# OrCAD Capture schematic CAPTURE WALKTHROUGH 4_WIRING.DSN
size A; title: Capture Walkthrough; rev: A; company: EMA Design Automation; note: EMA-12345678; note: 225 Tech Park Dr; note: Rochester, NY

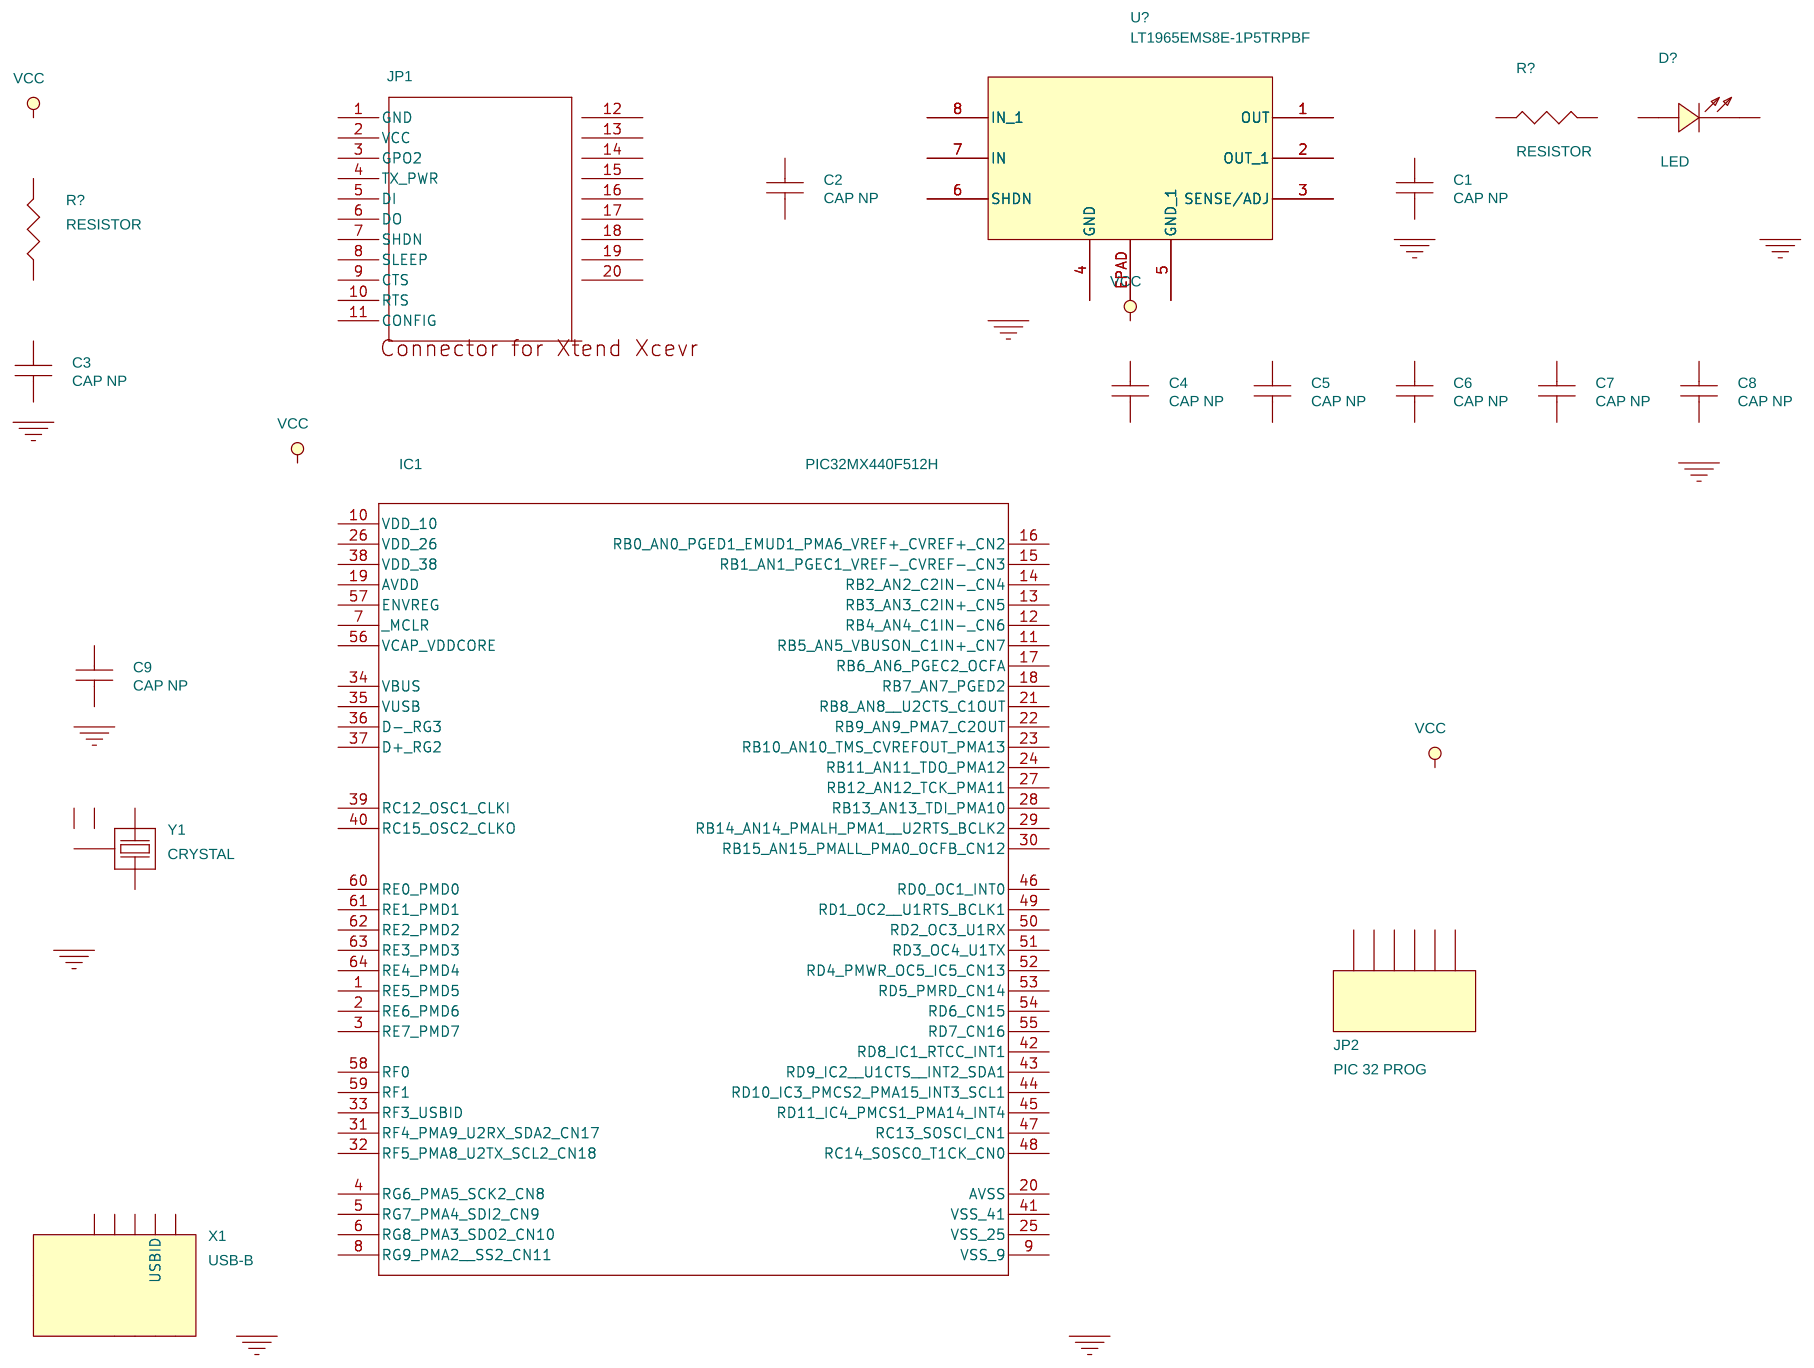
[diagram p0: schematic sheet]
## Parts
C1  CAP NP
C2  CAP NP
C3  CAP NP
C4  CAP NP
C5  CAP NP
C6  CAP NP
C7  CAP NP
C8  CAP NP
C9  CAP NP
D?#1  LED
IC1  PIC32MX440F512H  [sqfp-s-10x10-64]
JP1  XTEND-DIGI-MODEM  [xtend-digi-modem]
JP2  PIC 32 PROG  [1x06_lock]
R?#3  RESISTOR
R?#4  RESISTOR
U?#2  LT1965EMS8E-1P5TRPBF  [MSOP-EP08_3X3_ADI]
X1  USB-B  [USB-MICROB]
Y1  CRYSTAL  [crystal-smd]

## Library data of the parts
C1-C9 = CAP_NP
D?#1 = LED
IC1 = PIC32MX440F512H
JP1 = XTEND-DIGI-MODEM
JP2 = M06_LOCK
R?#3 R?#4 = RESISTOR
U?#2 = LT1965EMS8E-1P5TRPBF_0: 1.1A, Low Noise, Low Dropout Linear Regulator; Category: PMIC - Voltage Regulators - Linear; Distributor: Digi-Key; Distributor_PN: LT1965EMS8E-1.5#TRPBF-ND; MPN: LT1965EMS8E-1.5#TRPBF; Manufacturer: Analog Devices Inc; Mounting_Type: Surface Mount; Operating_Temperature: -40掳C ~ 125掳C; Package_Case: 8-TSSOP, 8-MSOP (0.118", 3.00mm Width) Exposed Pad; Package_Category: Tape & Reel (TR); ROHS: false; Status: Active; Supplier_Device_Package: 8-MSOP-EP
X1 = USB-MICROB
Y1 = CRYSTAL

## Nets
GND: U?#2.4(GND)
GND_1: U?#2.5(GND_1)

Not connected (* = marked no-connect by the designer): C1 1 2; C2 1 2; C3 1 2; C4 1 2; C5 1 2; C6 1 2; C7 1 2; C8 1 2; C9 1 2; D?#1 1(CATHODE) 2(ANODE); IC1 1(RE5_PMD5) 2(RE6_PMD6) 3(RE7_PMD7) 4(RG6_PMA5_SCK2_CN8) 5(RG7_PMA4_SDI2_CN9) 6(RG8_PMA3_SDO2_CN10) 7(_MCLR) 8(RG9_PMA2__SS2_CN11) 9(VSS) 10(VDD) 11(RB5_AN5_VBUSON_C1IN+_CN7) 12(RB4_AN4_C1IN-_CN6) 13(RB3_AN3_C2IN+_CN5) 14(RB2_AN2_C2IN-_CN4) 15(RB1_AN1_PGEC1_VREF-_CVREF-_CN3) 16(RB0_AN0_PGED1_EMUD1_PMA6_VREF+_CVREF+_CN2) 17(RB6_AN6_PGEC2_OCFA) 18(RB7_AN7_PGED2) 19(AVDD) 20(AVSS) 21(RB8_AN8__U2CTS_C1OUT) 22(RB9_AN9_PMA7_C2OUT) 23(RB10_AN10_TMS_CVREFOUT_PMA13) 24(RB11_AN11_TDO_PMA12) 25(VSS) 26(VDD) 27(RB12_AN12_TCK_PMA11) 28(RB13_AN13_TDI_PMA10) 29(RB14_AN14_PMALH_PMA1__U2RTS_BCLK2) 30(RB15_AN15_PMALL_PMA0_OCFB_CN12) 31(RF4_PMA9_U2RX_SDA2_CN17) 32(RF5_PMA8_U2TX_SCL2_CN18) 33(RF3_USBID) 34(VBUS) 35(VUSB) 36(D-_RG3) 37(D+_RG2) 38(VDD) 39(RC12_OSC1_CLKI) 40(RC15_OSC2_CLKO) 41(VSS) 42(RD8_IC1_RTCC_INT1) 43(RD9_IC2__U1CTS__INT2_SDA1) 44(RD10_IC3_PMCS2_PMA15_INT3_SCL1) 45(RD11_IC4_PMCS1_PMA14_INT4) 46(RD0_OC1_INT0) 47(RC13_SOSCI_CN1) 48(RC14_SOSCO_T1CK_CN0) 49(RD1_OC2__U1RTS_BCLK1) 50(RD2_OC3_U1RX) 51(RD3_OC4_U1TX) 52(RD4_PMWR_OC5_IC5_CN13) 53(RD5_PMRD_CN14) 54(RD6_CN15) 55(RD7_CN16) 56(VCAP_VDDCORE) 57(ENVREG) 58(RF0) 59(RF1) 60(RE0_PMD0) 61(RE1_PMD1) 62(RE2_PMD2) 63(RE3_PMD3) 64(RE4_PMD4); JP1 1(GND) 2(VCC) 3(GPO2) 4(TX_PWR) 5(DI) 6(DO) 7(SHDN) 8(SLEEP) 9(CTS) 10(RTS) 11(CONFIG) 12 13 14 15 16 17 18 19 20; JP2 1 2 3 4 5 6; R?#3 1 2; R?#4 1 2; U?#2 1(OUT) 2(OUT_1) 3(SENSE/ADJ) 6(SHDN) 7(IN) 8(IN_1) EPAD; X1 D+ D- GND ID(USBID) MT1 MT2 MT3 MT4 P_1 P_2 VBUS; Y1 1 2(GND) 3 4(GND)
